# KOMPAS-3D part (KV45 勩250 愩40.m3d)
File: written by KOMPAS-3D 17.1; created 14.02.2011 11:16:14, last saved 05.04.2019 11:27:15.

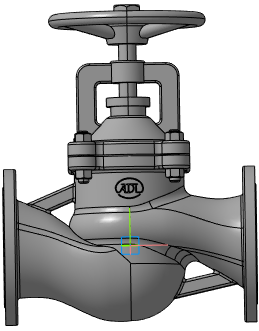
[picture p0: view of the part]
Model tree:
1. Плоскость XY
2. Плоскость ZX
3. Плоскость ZY
4. Ось X
5. Ось Y
6. Ось Z
7. Начало координат
8. Операция без истории:2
